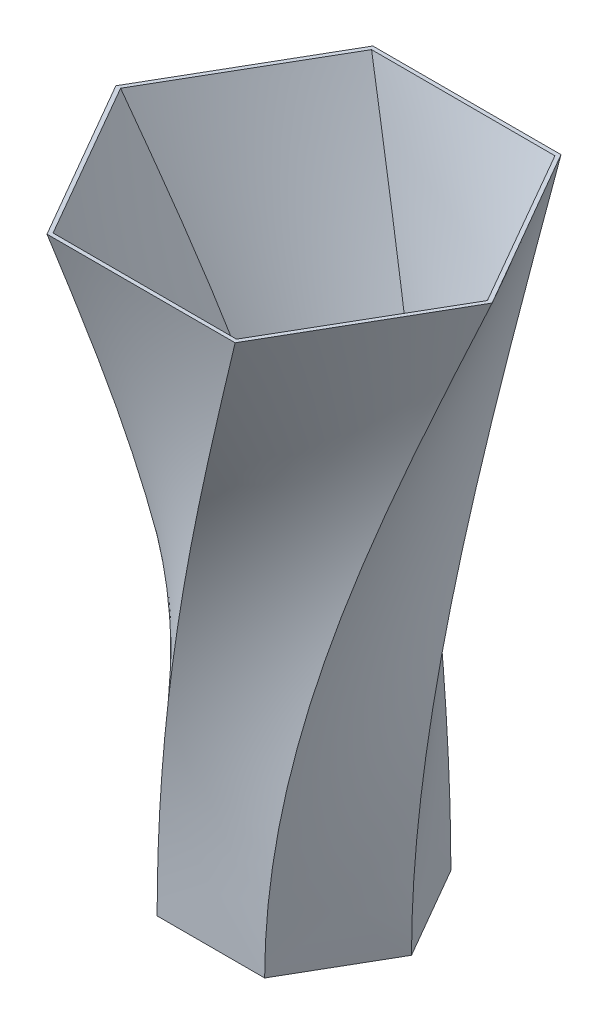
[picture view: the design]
ISO-10303-21;
HEADER;
FILE_DESCRIPTION(('STEP AP214'),'2;1');
FILE_NAME('part.step','',(''),(''),'','','');
FILE_SCHEMA(('AUTOMOTIVE_DESIGN { 1 0 10303 214 1 1 1 1 }'));
ENDSEC;
DATA;
#1=APPLICATION_CONTEXT('core data for automotive mechanical design processes');
#2=APPLICATION_PROTOCOL_DEFINITION('international standard','automotive_design',2000,#1);
#3=PRODUCT_CONTEXT('',#1,'mechanical');
#4=PRODUCT('Part','Part','',(#3));
#5=PRODUCT_RELATED_PRODUCT_CATEGORY('part','',(#4));
#6=PRODUCT_DEFINITION_FORMATION('','',#4);
#7=PRODUCT_DEFINITION_CONTEXT('part definition',#1,'design');
#8=PRODUCT_DEFINITION('design','',#6,#7);
#9=PRODUCT_DEFINITION_SHAPE('','',#8);
#10=(LENGTH_UNIT() NAMED_UNIT(*) SI_UNIT(.MILLI.,.METRE.));
#11=(NAMED_UNIT(*) PLANE_ANGLE_UNIT() SI_UNIT($,.RADIAN.));
#12=(NAMED_UNIT(*) SI_UNIT($,.STERADIAN.) SOLID_ANGLE_UNIT());
#13=UNCERTAINTY_MEASURE_WITH_UNIT(LENGTH_MEASURE(1.E-05),#10,'distance_accuracy_value','');
#14=(GEOMETRIC_REPRESENTATION_CONTEXT(3) GLOBAL_UNCERTAINTY_ASSIGNED_CONTEXT((#13)) GLOBAL_UNIT_ASSIGNED_CONTEXT((#10,
#11,#12)) REPRESENTATION_CONTEXT('',''));
#15=CARTESIAN_POINT('',(0.,0.,0.));
#16=DIRECTION('',(0.,0.,1.));
#17=DIRECTION('',(1.,0.,0.));
#18=AXIS2_PLACEMENT_3D('',#15,#16,#17);
#19=CARTESIAN_POINT('',(0.,325.,0.));
#20=DIRECTION('',(0.,1.,0.));
#21=DIRECTION('',(0.,0.,1.));
#22=AXIS2_PLACEMENT_3D('',#19,#20,#21);
#23=PLANE('',#22);
#24=CARTESIAN_POINT('',(98.6158699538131,325.,0.128719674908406));
#25=CARTESIAN_POINT('',(94.3670962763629,325.,-7.26044363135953));
#26=CARTESIAN_POINT('',(90.117498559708,325.,-14.6491331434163));
#27=CARTESIAN_POINT('',(81.6165698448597,325.,-29.4255150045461));
#28=CARTESIAN_POINT('',(77.3652388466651,325.,-36.8132073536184));
#29=CARTESIAN_POINT('',(65.2183604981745,325.,-57.9152707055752));
#30=CARTESIAN_POINT('',(57.3205883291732,325.000000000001,-71.6283610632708));
#31=CARTESIAN_POINT('',(49.4194094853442,325.,-85.3394887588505));
#32=B_SPLINE_CURVE_WITH_KNOTS('',3,(#24,#25,#26,#27,#28,#29,#30,#31),.UNSPECIFIED.,.F.,.F.,(4,2,
2,4),(0.,25.5708096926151,51.1416194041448,98.6159570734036),.UNSPECIFIED.);
#33=CARTESIAN_POINT('',(98.6158699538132,325.,0.12871967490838));
#34=VERTEX_POINT('',#33);
#35=CARTESIAN_POINT('',(49.4194094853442,325.,-85.3394887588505));
#36=VERTEX_POINT('',#35);
#37=EDGE_CURVE('E525',#34,#36,#32,.T.);
#38=ORIENTED_EDGE('',*,*,#37,.F.);
#39=CARTESIAN_POINT('',(49.196460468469,325.,85.4682084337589));
#40=CARTESIAN_POINT('',(53.4712767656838,325.,78.0940808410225));
#41=CARTESIAN_POINT('',(57.7452707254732,325.,70.7194765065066));
#42=CARTESIAN_POINT('',(66.291528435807,325.,55.9692653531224));
#43=CARTESIAN_POINT('',(70.5637921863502,325.,48.5936585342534));
#44=CARTESIAN_POINT('',(82.765275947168,325.,27.523121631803));
#45=CARTESIAN_POINT('',(90.6922744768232,324.999999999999,13.8269051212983));
#46=CARTESIAN_POINT('',(98.6158699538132,325.,0.128719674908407));
#47=B_SPLINE_CURVE_WITH_KNOTS('',3,(#39,#40,#41,#42,#43,#44,#45,#46),.UNSPECIFIED.,.F.,.F.,(4,2,
2,4),(0.,25.5708096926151,51.1416194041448,98.6159570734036),.UNSPECIFIED.);
#48=CARTESIAN_POINT('',(49.196460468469,325.,85.4682084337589));
#49=VERTEX_POINT('',#48);
#50=EDGE_CURVE('E190',#49,#34,#47,.T.);
#51=ORIENTED_EDGE('',*,*,#50,.F.);
#52=CARTESIAN_POINT('',(-49.4194094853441,325.,85.3394887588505));
#53=CARTESIAN_POINT('',(-40.8958195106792,325.,85.3545244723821));
#54=CARTESIAN_POINT('',(-32.3722278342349,325.,85.3686096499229));
#55=CARTESIAN_POINT('',(-15.3250414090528,325.,85.3947803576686));
#56=CARTESIAN_POINT('',(-6.80144666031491,325.,85.4068658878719));
#57=CARTESIAN_POINT('',(17.5469154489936,325.,85.4383923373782));
#58=CARTESIAN_POINT('',(33.3716861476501,325.,85.4552661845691));
#59=CARTESIAN_POINT('',(49.196460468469,325.,85.468208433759));
#60=B_SPLINE_CURVE_WITH_KNOTS('',3,(#52,#53,#54,#55,#56,#57,#58,#59),.UNSPECIFIED.,.F.,.F.,(4,2,
2,4),(0.,25.5708096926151,51.1416194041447,98.6159570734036),.UNSPECIFIED.);
#61=CARTESIAN_POINT('',(-49.4194094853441,325.,85.3394887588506));
#62=VERTEX_POINT('',#61);
#63=EDGE_CURVE('E92',#62,#49,#60,.T.);
#64=ORIENTED_EDGE('',*,*,#63,.F.);
#65=CARTESIAN_POINT('',(-98.6158699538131,325.,-0.128719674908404));
#66=CARTESIAN_POINT('',(-94.3670962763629,325.,7.2604436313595));
#67=CARTESIAN_POINT('',(-90.117498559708,325.,14.6491331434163));
#68=CARTESIAN_POINT('',(-81.6165698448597,325.,29.4255150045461));
#69=CARTESIAN_POINT('',(-77.365238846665,325.,36.8132073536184));
#70=CARTESIAN_POINT('',(-65.2183604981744,325.,57.9152707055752));
#71=CARTESIAN_POINT('',(-57.3205883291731,325.000000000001,71.6283610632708));
#72=CARTESIAN_POINT('',(-49.419409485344,325.,85.3394887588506));
#73=B_SPLINE_CURVE_WITH_KNOTS('',3,(#65,#66,#67,#68,#69,#70,#71,#72),.UNSPECIFIED.,.F.,.F.,(4,2,
2,4),(0.,25.5708096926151,51.1416194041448,98.6159570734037),.UNSPECIFIED.);
#74=CARTESIAN_POINT('',(-98.6158699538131,325.,-0.128719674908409));
#75=VERTEX_POINT('',#74);
#76=EDGE_CURVE('E501',#75,#62,#73,.T.);
#77=ORIENTED_EDGE('',*,*,#76,.F.);
#78=CARTESIAN_POINT('',(-49.196460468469,325.,-85.468208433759));
#79=CARTESIAN_POINT('',(-53.4712767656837,325.,-78.0940808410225));
#80=CARTESIAN_POINT('',(-57.7452707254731,325.,-70.7194765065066));
#81=CARTESIAN_POINT('',(-66.2915284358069,325.,-55.9692653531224));
#82=CARTESIAN_POINT('',(-70.5637921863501,325.,-48.5936585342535));
#83=CARTESIAN_POINT('',(-82.765275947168,325.,-27.523121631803));
#84=CARTESIAN_POINT('',(-90.6922744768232,325.,-13.8269051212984));
#85=CARTESIAN_POINT('',(-98.6158699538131,325.,-0.128719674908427));
#86=B_SPLINE_CURVE_WITH_KNOTS('',3,(#78,#79,#80,#81,#82,#83,#84,#85),.UNSPECIFIED.,.F.,.F.,(4,2,
2,4),(0.,25.5708096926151,51.1416194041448,98.6159570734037),.UNSPECIFIED.);
#87=CARTESIAN_POINT('',(-49.196460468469,325.,-85.4682084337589));
#88=VERTEX_POINT('',#87);
#89=EDGE_CURVE('E548',#88,#75,#86,.T.);
#90=ORIENTED_EDGE('',*,*,#89,.F.);
#91=CARTESIAN_POINT('',(49.4194094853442,325.,-85.3394887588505));
#92=CARTESIAN_POINT('',(40.8958195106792,325.,-85.354524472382));
#93=CARTESIAN_POINT('',(32.3722278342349,325.,-85.3686096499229));
#94=CARTESIAN_POINT('',(15.3250414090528,325.,-85.3947803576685));
#95=CARTESIAN_POINT('',(6.80144666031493,325.,-85.4068658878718));
#96=CARTESIAN_POINT('',(-17.5469154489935,325.,-85.4383923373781));
#97=CARTESIAN_POINT('',(-33.37168614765,325.,-85.4552661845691));
#98=CARTESIAN_POINT('',(-49.196460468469,325.,-85.4682084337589));
#99=B_SPLINE_CURVE_WITH_KNOTS('',3,(#91,#92,#93,#94,#95,#96,#97,#98),.UNSPECIFIED.,.F.,.F.,(4,2,
2,4),(0.,25.5708096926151,51.1416194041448,98.6159570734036),.UNSPECIFIED.);
#100=EDGE_CURVE('E542',#36,#88,#99,.T.);
#101=ORIENTED_EDGE('',*,*,#100,.F.);
#102=EDGE_LOOP('',(#38,#51,#64,#77,#90,#101));
#103=FACE_BOUND('',#102,.T.);
#104=DIRECTION('',(-0.5,0.,-0.866025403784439));
#105=VECTOR('',#104,1.);
#106=CARTESIAN_POINT('',(101.036297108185,325.,0.));
#107=LINE('',#106,#105);
#108=CARTESIAN_POINT('',(101.036297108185,325.,0.));
#109=VERTEX_POINT('',#108);
#110=CARTESIAN_POINT('',(50.5181485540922,325.,-87.5));
#111=VERTEX_POINT('',#110);
#112=EDGE_CURVE('E471',#109,#111,#107,.T.);
#113=ORIENTED_EDGE('',*,*,#112,.T.);
#114=DIRECTION('',(-1.,0.,0.));
#115=VECTOR('',#114,1.);
#116=CARTESIAN_POINT('',(50.5181485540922,325.,-87.5));
#117=LINE('',#116,#115);
#118=CARTESIAN_POINT('',(-50.5181485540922,325.,-87.5));
#119=VERTEX_POINT('',#118);
#120=EDGE_CURVE('E265',#111,#119,#117,.T.);
#121=ORIENTED_EDGE('',*,*,#120,.T.);
#122=DIRECTION('',(-0.5,0.,0.866025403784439));
#123=VECTOR('',#122,1.);
#124=CARTESIAN_POINT('',(-50.5181485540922,325.,-87.5));
#125=LINE('',#124,#123);
#126=CARTESIAN_POINT('',(-101.036297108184,325.,0.));
#127=VERTEX_POINT('',#126);
#128=EDGE_CURVE('E704',#119,#127,#125,.T.);
#129=ORIENTED_EDGE('',*,*,#128,.T.);
#130=DIRECTION('',(0.5,0.,0.866025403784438));
#131=VECTOR('',#130,1.);
#132=CARTESIAN_POINT('',(-101.036297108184,325.,0.));
#133=LINE('',#132,#131);
#134=CARTESIAN_POINT('',(-50.5181485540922,325.,87.5));
#135=VERTEX_POINT('',#134);
#136=EDGE_CURVE('E711',#127,#135,#133,.T.);
#137=ORIENTED_EDGE('',*,*,#136,.T.);
#138=DIRECTION('',(1.,0.,0.));
#139=VECTOR('',#138,1.);
#140=CARTESIAN_POINT('',(-50.5181485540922,325.,87.5));
#141=LINE('',#140,#139);
#142=CARTESIAN_POINT('',(50.5181485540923,325.,87.5));
#143=VERTEX_POINT('',#142);
#144=EDGE_CURVE('E84',#135,#143,#141,.T.);
#145=ORIENTED_EDGE('',*,*,#144,.T.);
#146=DIRECTION('',(0.5,0.,-0.866025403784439));
#147=VECTOR('',#146,1.);
#148=CARTESIAN_POINT('',(50.5181485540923,325.,87.5));
#149=LINE('',#148,#147);
#150=EDGE_CURVE('E12',#143,#109,#149,.T.);
#151=ORIENTED_EDGE('',*,*,#150,.T.);
#152=EDGE_LOOP('',(#113,#121,#129,#137,#145,#151));
#153=FACE_BOUND('',#152,.T.);
#154=ADVANCED_FACE('F74',(#103,#153),#23,.T.);
#155=CARTESIAN_POINT('',(0.,0.,0.));
#156=DIRECTION('',(0.,1.,0.));
#157=DIRECTION('',(0.,0.,1.));
#158=AXIS2_PLACEMENT_3D('',#155,#156,#157);
#159=PLANE('',#158);
#160=DIRECTION('',(-0.5,0.,-0.866025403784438));
#161=VECTOR('',#160,1.);
#162=CARTESIAN_POINT('',(57.7350269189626,0.,0.));
#163=LINE('',#162,#161);
#164=CARTESIAN_POINT('',(57.7350269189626,0.,0.));
#165=VERTEX_POINT('',#164);
#166=CARTESIAN_POINT('',(28.8675134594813,0.,-50.));
#167=VERTEX_POINT('',#166);
#168=EDGE_CURVE('E395',#165,#167,#163,.T.);
#169=ORIENTED_EDGE('',*,*,#168,.F.);
#170=DIRECTION('',(0.5,0.,-0.866025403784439));
#171=VECTOR('',#170,1.);
#172=CARTESIAN_POINT('',(28.8675134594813,0.,50.));
#173=LINE('',#172,#171);
#174=CARTESIAN_POINT('',(28.8675134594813,0.,50.));
#175=VERTEX_POINT('',#174);
#176=EDGE_CURVE('E398',#175,#165,#173,.T.);
#177=ORIENTED_EDGE('',*,*,#176,.F.);
#178=DIRECTION('',(1.,0.,0.));
#179=VECTOR('',#178,1.);
#180=CARTESIAN_POINT('',(-28.8675134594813,0.,50.));
#181=LINE('',#180,#179);
#182=CARTESIAN_POINT('',(-28.8675134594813,0.,50.));
#183=VERTEX_POINT('',#182);
#184=EDGE_CURVE('E403',#183,#175,#181,.T.);
#185=ORIENTED_EDGE('',*,*,#184,.F.);
#186=DIRECTION('',(0.5,0.,0.866025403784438));
#187=VECTOR('',#186,1.);
#188=CARTESIAN_POINT('',(-57.7350269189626,0.,0.));
#189=LINE('',#188,#187);
#190=CARTESIAN_POINT('',(-57.7350269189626,0.,0.));
#191=VERTEX_POINT('',#190);
#192=EDGE_CURVE('E458',#191,#183,#189,.T.);
#193=ORIENTED_EDGE('',*,*,#192,.F.);
#194=DIRECTION('',(-0.5,0.,0.866025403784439));
#195=VECTOR('',#194,1.);
#196=CARTESIAN_POINT('',(-28.8675134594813,0.,-50.));
#197=LINE('',#196,#195);
#198=CARTESIAN_POINT('',(-28.8675134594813,0.,-50.));
#199=VERTEX_POINT('',#198);
#200=EDGE_CURVE('E345',#199,#191,#197,.T.);
#201=ORIENTED_EDGE('',*,*,#200,.F.);
#202=DIRECTION('',(-1.,0.,0.));
#203=VECTOR('',#202,1.);
#204=CARTESIAN_POINT('',(28.8675134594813,0.,-50.));
#205=LINE('',#204,#203);
#206=EDGE_CURVE('E322',#167,#199,#205,.T.);
#207=ORIENTED_EDGE('',*,*,#206,.F.);
#208=EDGE_LOOP('',(#169,#177,#185,#193,#201,#207));
#209=FACE_BOUND('',#208,.T.);
#210=ADVANCED_FACE('F415',(#209),#159,.F.);
#211=CARTESIAN_POINT('',(-28.8675134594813,0.,50.));
#212=CARTESIAN_POINT('',(-28.8675134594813,112.216721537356,50.));
#213=CARTESIAN_POINT('',(10.8253175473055,218.608360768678,68.75));
#214=CARTESIAN_POINT('',(50.5181485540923,325.,87.5));
#215=CARTESIAN_POINT('',(-9.62250448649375,0.,50.));
#216=CARTESIAN_POINT('',(-9.62250448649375,112.216721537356,50.));
#217=CARTESIAN_POINT('',(28.8675134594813,218.608360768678,54.1666666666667));
#218=CARTESIAN_POINT('',(67.3575314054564,325.,58.3333333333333));
#219=CARTESIAN_POINT('',(9.62250448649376,0.,50.));
#220=CARTESIAN_POINT('',(9.62250448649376,112.216721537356,50.));
#221=CARTESIAN_POINT('',(46.9097093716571,218.608360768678,39.5833333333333));
#222=CARTESIAN_POINT('',(84.1969142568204,325.,29.1666666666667));
#223=CARTESIAN_POINT('',(28.8675134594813,0.,50.));
#224=CARTESIAN_POINT('',(28.8675134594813,112.216721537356,50.));
#225=CARTESIAN_POINT('',(64.9519052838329,218.608360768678,25.));
#226=CARTESIAN_POINT('',(101.036297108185,325.,0.));
#227=B_SPLINE_SURFACE_WITH_KNOTS('',3,3,((#211,#212,#213,#214),(#215,#216,#217,#218),(#219,#220,
#221,#222),(#223,#224,#225,#226)),.UNSPECIFIED.,.F.,.F.,.F.,(4,4),(4,4),(0.,1.),(0.,1.),.UNSPECIFIED.);
#228=CARTESIAN_POINT('',(28.8675134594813,0.,50.));
#229=CARTESIAN_POINT('',(28.8675134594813,112.216721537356,50.));
#230=CARTESIAN_POINT('',(64.9519052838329,218.608360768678,25.));
#231=CARTESIAN_POINT('',(101.036297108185,325.,0.));
#232=B_SPLINE_CURVE_WITH_KNOTS('',3,(#228,#229,#230,#231),.UNSPECIFIED.,.F.,.F.,(4,4),(0.,1.),.UNSPECIFIED.);
#233=EDGE_CURVE('E467',#175,#109,#232,.T.);
#234=CARTESIAN_POINT('',(-28.8675134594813,0.,50.));
#235=CARTESIAN_POINT('',(-28.8675134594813,112.216721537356,50.));
#236=CARTESIAN_POINT('',(10.8253175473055,218.608360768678,68.75));
#237=CARTESIAN_POINT('',(50.5181485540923,325.,87.5));
#238=B_SPLINE_CURVE_WITH_KNOTS('',3,(#234,#235,#236,#237),.UNSPECIFIED.,.F.,.F.,(4,4),(0.,1.),.UNSPECIFIED.);
#239=EDGE_CURVE('E402',#143,#183,#238,.F.);
#240=ORIENTED_EDGE('',*,*,#184,.T.);
#241=ORIENTED_EDGE('',*,*,#233,.T.);
#242=ORIENTED_EDGE('',*,*,#150,.F.);
#243=ORIENTED_EDGE('',*,*,#239,.T.);
#244=EDGE_LOOP('',(#240,#241,#242,#243));
#245=FACE_BOUND('',#244,.T.);
#246=ADVANCED_FACE('F234',(#245),#227,.T.);
#247=CARTESIAN_POINT('',(28.8675134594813,0.,50.));
#248=CARTESIAN_POINT('',(28.8675134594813,112.216721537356,50.));
#249=CARTESIAN_POINT('',(64.9519052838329,218.608360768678,25.));
#250=CARTESIAN_POINT('',(101.036297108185,325.,0.));
#251=CARTESIAN_POINT('',(38.4900179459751,0.,33.3333333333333));
#252=CARTESIAN_POINT('',(38.4900179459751,112.216721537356,33.3333333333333));
#253=CARTESIAN_POINT('',(61.3434661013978,218.608360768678,2.08333333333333));
#254=CARTESIAN_POINT('',(84.1969142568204,325.,-29.1666666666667));
#255=CARTESIAN_POINT('',(48.1125224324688,0.,16.6666666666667));
#256=CARTESIAN_POINT('',(48.1125224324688,112.216721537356,16.6666666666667));
#257=CARTESIAN_POINT('',(57.7350269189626,218.608360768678,-20.8333333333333));
#258=CARTESIAN_POINT('',(67.3575314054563,325.,-58.3333333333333));
#259=CARTESIAN_POINT('',(57.7350269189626,0.,0.));
#260=CARTESIAN_POINT('',(57.7350269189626,112.216721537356,0.));
#261=CARTESIAN_POINT('',(54.1265877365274,218.608360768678,-43.75));
#262=CARTESIAN_POINT('',(50.5181485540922,325.,-87.5));
#263=B_SPLINE_SURFACE_WITH_KNOTS('',3,3,((#247,#248,#249,#250),(#251,#252,#253,#254),(#255,#256,
#257,#258),(#259,#260,#261,#262)),.UNSPECIFIED.,.F.,.F.,.F.,(4,4),(4,4),(0.,1.),(0.,1.),.UNSPECIFIED.);
#264=CARTESIAN_POINT('',(57.7350269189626,0.,0.));
#265=CARTESIAN_POINT('',(57.7350269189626,112.216721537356,0.));
#266=CARTESIAN_POINT('',(54.1265877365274,218.608360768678,-43.75));
#267=CARTESIAN_POINT('',(50.5181485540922,325.,-87.5));
#268=B_SPLINE_CURVE_WITH_KNOTS('',3,(#264,#265,#266,#267),.UNSPECIFIED.,.F.,.F.,(4,4),(0.,1.),.UNSPECIFIED.);
#269=EDGE_CURVE('E309',#165,#111,#268,.T.);
#270=ORIENTED_EDGE('',*,*,#176,.T.);
#271=ORIENTED_EDGE('',*,*,#269,.T.);
#272=ORIENTED_EDGE('',*,*,#112,.F.);
#273=ORIENTED_EDGE('',*,*,#233,.F.);
#274=EDGE_LOOP('',(#270,#271,#272,#273));
#275=FACE_BOUND('',#274,.T.);
#276=ADVANCED_FACE('F227',(#275),#263,.T.);
#277=CARTESIAN_POINT('',(-57.7350269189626,0.,0.));
#278=CARTESIAN_POINT('',(-57.7350269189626,112.216721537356,0.));
#279=CARTESIAN_POINT('',(-54.1265877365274,218.608360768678,43.75));
#280=CARTESIAN_POINT('',(-50.5181485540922,325.,87.5));
#281=CARTESIAN_POINT('',(-48.1125224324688,0.,16.6666666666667));
#282=CARTESIAN_POINT('',(-48.1125224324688,112.216721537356,16.6666666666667));
#283=CARTESIAN_POINT('',(-32.4759526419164,218.608360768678,52.0833333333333));
#284=CARTESIAN_POINT('',(-16.839382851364,325.,87.5));
#285=CARTESIAN_POINT('',(-38.490017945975,0.,33.3333333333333));
#286=CARTESIAN_POINT('',(-38.490017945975,112.216721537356,33.3333333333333));
#287=CARTESIAN_POINT('',(-10.8253175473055,218.608360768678,60.4166666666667));
#288=CARTESIAN_POINT('',(16.8393828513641,325.,87.5));
#289=CARTESIAN_POINT('',(-28.8675134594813,0.,50.));
#290=CARTESIAN_POINT('',(-28.8675134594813,112.216721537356,50.));
#291=CARTESIAN_POINT('',(10.8253175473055,218.608360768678,68.75));
#292=CARTESIAN_POINT('',(50.5181485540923,325.,87.5));
#293=B_SPLINE_SURFACE_WITH_KNOTS('',3,3,((#277,#278,#279,#280),(#281,#282,#283,#284),(#285,#286,
#287,#288),(#289,#290,#291,#292)),.UNSPECIFIED.,.F.,.F.,.F.,(4,4),(4,4),(0.,1.),(0.,1.),.UNSPECIFIED.);
#294=CARTESIAN_POINT('',(-57.7350269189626,0.,0.));
#295=CARTESIAN_POINT('',(-57.7350269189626,112.216721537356,0.));
#296=CARTESIAN_POINT('',(-54.1265877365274,218.608360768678,43.75));
#297=CARTESIAN_POINT('',(-50.5181485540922,325.,87.5));
#298=B_SPLINE_CURVE_WITH_KNOTS('',3,(#294,#295,#296,#297),.UNSPECIFIED.,.F.,.F.,(4,4),(0.,1.),.UNSPECIFIED.);
#299=EDGE_CURVE('E333',#191,#135,#298,.T.);
#300=ORIENTED_EDGE('',*,*,#192,.T.);
#301=ORIENTED_EDGE('',*,*,#239,.F.);
#302=ORIENTED_EDGE('',*,*,#144,.F.);
#303=ORIENTED_EDGE('',*,*,#299,.F.);
#304=EDGE_LOOP('',(#300,#301,#302,#303));
#305=FACE_BOUND('',#304,.T.);
#306=ADVANCED_FACE('F233',(#305),#293,.T.);
#307=CARTESIAN_POINT('',(57.7350269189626,0.,0.));
#308=CARTESIAN_POINT('',(57.7350269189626,112.216721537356,0.));
#309=CARTESIAN_POINT('',(54.1265877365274,218.608360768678,-43.75));
#310=CARTESIAN_POINT('',(50.5181485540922,325.,-87.5));
#311=CARTESIAN_POINT('',(48.1125224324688,0.,-16.6666666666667));
#312=CARTESIAN_POINT('',(48.1125224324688,112.216721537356,-16.6666666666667));
#313=CARTESIAN_POINT('',(32.4759526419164,218.608360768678,-52.0833333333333));
#314=CARTESIAN_POINT('',(16.8393828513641,325.,-87.5));
#315=CARTESIAN_POINT('',(38.4900179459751,0.,-33.3333333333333));
#316=CARTESIAN_POINT('',(38.4900179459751,112.216721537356,-33.3333333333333));
#317=CARTESIAN_POINT('',(10.8253175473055,218.608360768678,-60.4166666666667));
#318=CARTESIAN_POINT('',(-16.8393828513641,325.,-87.5));
#319=CARTESIAN_POINT('',(28.8675134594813,0.,-50.));
#320=CARTESIAN_POINT('',(28.8675134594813,112.216721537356,-50.));
#321=CARTESIAN_POINT('',(-10.8253175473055,218.608360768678,-68.75));
#322=CARTESIAN_POINT('',(-50.5181485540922,325.,-87.5));
#323=B_SPLINE_SURFACE_WITH_KNOTS('',3,3,((#307,#308,#309,#310),(#311,#312,#313,#314),(#315,#316,
#317,#318),(#319,#320,#321,#322)),.UNSPECIFIED.,.F.,.F.,.F.,(4,4),(4,4),(0.,1.),(0.,1.),.UNSPECIFIED.);
#324=CARTESIAN_POINT('',(28.8675134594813,0.,-50.));
#325=CARTESIAN_POINT('',(28.8675134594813,112.216721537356,-50.));
#326=CARTESIAN_POINT('',(-10.8253175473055,218.608360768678,-68.75));
#327=CARTESIAN_POINT('',(-50.5181485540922,325.,-87.5));
#328=B_SPLINE_CURVE_WITH_KNOTS('',3,(#324,#325,#326,#327),.UNSPECIFIED.,.F.,.F.,(4,4),(0.,1.),.UNSPECIFIED.);
#329=EDGE_CURVE('E301',#167,#119,#328,.T.);
#330=ORIENTED_EDGE('',*,*,#168,.T.);
#331=ORIENTED_EDGE('',*,*,#329,.T.);
#332=ORIENTED_EDGE('',*,*,#120,.F.);
#333=ORIENTED_EDGE('',*,*,#269,.F.);
#334=EDGE_LOOP('',(#330,#331,#332,#333));
#335=FACE_BOUND('',#334,.T.);
#336=ADVANCED_FACE('F271',(#335),#323,.T.);
#337=CARTESIAN_POINT('',(28.8675134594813,0.,-50.));
#338=CARTESIAN_POINT('',(28.8675134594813,112.216721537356,-50.));
#339=CARTESIAN_POINT('',(-10.8253175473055,218.608360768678,-68.75));
#340=CARTESIAN_POINT('',(-50.5181485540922,325.,-87.5));
#341=CARTESIAN_POINT('',(9.62250448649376,0.,-50.));
#342=CARTESIAN_POINT('',(9.62250448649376,112.216721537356,-50.));
#343=CARTESIAN_POINT('',(-28.8675134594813,218.608360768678,-54.1666666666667));
#344=CARTESIAN_POINT('',(-67.3575314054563,325.,-58.3333333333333));
#345=CARTESIAN_POINT('',(-9.62250448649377,0.,-50.));
#346=CARTESIAN_POINT('',(-9.62250448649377,112.216721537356,-50.));
#347=CARTESIAN_POINT('',(-46.9097093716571,218.608360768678,-39.5833333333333));
#348=CARTESIAN_POINT('',(-84.1969142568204,325.,-29.1666666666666));
#349=CARTESIAN_POINT('',(-28.8675134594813,0.,-50.));
#350=CARTESIAN_POINT('',(-28.8675134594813,112.216721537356,-50.));
#351=CARTESIAN_POINT('',(-64.9519052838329,218.608360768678,-25.));
#352=CARTESIAN_POINT('',(-101.036297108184,325.,0.));
#353=B_SPLINE_SURFACE_WITH_KNOTS('',3,3,((#337,#338,#339,#340),(#341,#342,#343,#344),(#345,#346,
#347,#348),(#349,#350,#351,#352)),.UNSPECIFIED.,.F.,.F.,.F.,(4,4),(4,4),(0.,1.),(0.,1.),.UNSPECIFIED.);
#354=CARTESIAN_POINT('',(-28.8675134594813,0.,-50.));
#355=CARTESIAN_POINT('',(-28.8675134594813,112.216721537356,-50.));
#356=CARTESIAN_POINT('',(-64.9519052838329,218.608360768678,-25.));
#357=CARTESIAN_POINT('',(-101.036297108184,325.,0.));
#358=B_SPLINE_CURVE_WITH_KNOTS('',3,(#354,#355,#356,#357),.UNSPECIFIED.,.F.,.F.,(4,4),(0.,1.),.UNSPECIFIED.);
#359=EDGE_CURVE('E308',#199,#127,#358,.T.);
#360=ORIENTED_EDGE('',*,*,#206,.T.);
#361=ORIENTED_EDGE('',*,*,#359,.T.);
#362=ORIENTED_EDGE('',*,*,#128,.F.);
#363=ORIENTED_EDGE('',*,*,#329,.F.);
#364=EDGE_LOOP('',(#360,#361,#362,#363));
#365=FACE_BOUND('',#364,.T.);
#366=ADVANCED_FACE('F282',(#365),#353,.T.);
#367=CARTESIAN_POINT('',(-28.8675134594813,0.,-50.));
#368=CARTESIAN_POINT('',(-28.8675134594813,112.216721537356,-50.));
#369=CARTESIAN_POINT('',(-64.9519052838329,218.608360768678,-25.));
#370=CARTESIAN_POINT('',(-101.036297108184,325.,0.));
#371=CARTESIAN_POINT('',(-38.4900179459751,0.,-33.3333333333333));
#372=CARTESIAN_POINT('',(-38.4900179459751,112.216721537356,-33.3333333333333));
#373=CARTESIAN_POINT('',(-61.3434661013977,218.608360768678,-2.08333333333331));
#374=CARTESIAN_POINT('',(-84.1969142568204,325.,29.1666666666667));
#375=CARTESIAN_POINT('',(-48.1125224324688,0.,-16.6666666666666));
#376=CARTESIAN_POINT('',(-48.1125224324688,112.216721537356,-16.6666666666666));
#377=CARTESIAN_POINT('',(-57.7350269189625,218.608360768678,20.8333333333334));
#378=CARTESIAN_POINT('',(-67.3575314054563,325.,58.3333333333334));
#379=CARTESIAN_POINT('',(-57.7350269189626,0.,0.));
#380=CARTESIAN_POINT('',(-57.7350269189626,112.216721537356,0.));
#381=CARTESIAN_POINT('',(-54.1265877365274,218.608360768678,43.75));
#382=CARTESIAN_POINT('',(-50.5181485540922,325.,87.5));
#383=B_SPLINE_SURFACE_WITH_KNOTS('',3,3,((#367,#368,#369,#370),(#371,#372,#373,#374),(#375,#376,
#377,#378),(#379,#380,#381,#382)),.UNSPECIFIED.,.F.,.F.,.F.,(4,4),(4,4),(0.,1.),(0.,1.),.UNSPECIFIED.);
#384=ORIENTED_EDGE('',*,*,#200,.T.);
#385=ORIENTED_EDGE('',*,*,#299,.T.);
#386=ORIENTED_EDGE('',*,*,#136,.F.);
#387=ORIENTED_EDGE('',*,*,#359,.F.);
#388=EDGE_LOOP('',(#384,#385,#386,#387));
#389=FACE_BOUND('',#388,.T.);
#390=ADVANCED_FACE('F351',(#389),#383,.T.);
#391=CARTESIAN_POINT('',(0.,7.5,0.));
#392=DIRECTION('',(0.,1.,0.));
#393=DIRECTION('',(0.,0.,1.));
#394=AXIS2_PLACEMENT_3D('',#391,#392,#393);
#395=PLANE('',#394);
#396=CARTESIAN_POINT('',(55.4202012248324,7.5,-0.0622549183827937));
#397=CARTESIAN_POINT('',(50.7929049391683,7.5,-8.05630691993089));
#398=CARTESIAN_POINT('',(46.1655888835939,7.5,-16.0503474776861));
#399=CARTESIAN_POINT('',(36.9109172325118,7.5,-32.0384057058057));
#400=CARTESIAN_POINT('',(32.2835616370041,7.5,-40.0324233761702));
#401=CARTESIAN_POINT('',(27.6561862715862,7.5,-48.0264296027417));
#402=B_SPLINE_CURVE_WITH_KNOTS('',3,(#396,#397,#398,#399,#400,#401),.UNSPECIFIED.,.F.,.F.,(4,2,
4),(0.,27.7101180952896,55.4202361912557),.UNSPECIFIED.);
#403=CARTESIAN_POINT('',(55.4202012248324,7.5,-0.0622549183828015));
#404=VERTEX_POINT('',#403);
#405=CARTESIAN_POINT('',(27.6561862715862,7.5,-48.0264296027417));
#406=VERTEX_POINT('',#405);
#407=EDGE_CURVE('E565',#404,#406,#402,.T.);
#408=ORIENTED_EDGE('',*,*,#407,.T.);
#409=CARTESIAN_POINT('',(27.6561862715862,7.5,-48.0264296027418));
#410=CARTESIAN_POINT('',(18.4194860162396,7.5,-48.0160994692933));
#411=CARTESIAN_POINT('',(9.18278578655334,7.5,-48.0057464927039));
#412=CARTESIAN_POINT('',(-9.29061462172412,7.5,-47.9849948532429));
#413=CARTESIAN_POINT('',(-18.5273148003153,7.5,-47.9745961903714));
#414=CARTESIAN_POINT('',(-27.7640149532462,7.5,-47.9641746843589));
#415=B_SPLINE_CURVE_WITH_KNOTS('',3,(#409,#410,#411,#412,#413,#414),.UNSPECIFIED.,.F.,.F.,(4,2,
4),(0.,27.7101180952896,55.4202361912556),.UNSPECIFIED.);
#416=CARTESIAN_POINT('',(-27.7640149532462,7.5,-47.9641746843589));
#417=VERTEX_POINT('',#416);
#418=EDGE_CURVE('E202',#406,#417,#415,.T.);
#419=ORIENTED_EDGE('',*,*,#418,.T.);
#420=CARTESIAN_POINT('',(-27.7640149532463,7.5,-47.9641746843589));
#421=CARTESIAN_POINT('',(-32.3734189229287,7.5,-39.9597925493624));
#422=CARTESIAN_POINT('',(-36.9828030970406,7.5,-31.9553990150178));
#423=CARTESIAN_POINT('',(-46.201531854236,7.5,-15.9465891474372));
#424=CARTESIAN_POINT('',(-50.8108764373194,7.5,-7.94217281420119));
#425=CARTESIAN_POINT('',(-55.4202012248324,7.5,0.0622549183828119));
#426=B_SPLINE_CURVE_WITH_KNOTS('',3,(#420,#421,#422,#423,#424,#425),.UNSPECIFIED.,.F.,.F.,(4,2,
4),(0.,27.7101180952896,55.4202361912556),.UNSPECIFIED.);
#427=CARTESIAN_POINT('',(-55.4202012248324,7.5,0.0622549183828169));
#428=VERTEX_POINT('',#427);
#429=EDGE_CURVE('E568',#417,#428,#426,.T.);
#430=ORIENTED_EDGE('',*,*,#429,.T.);
#431=CARTESIAN_POINT('',(-55.4202012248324,7.5,0.0622549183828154));
#432=CARTESIAN_POINT('',(-50.7929049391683,7.5,8.05630691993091));
#433=CARTESIAN_POINT('',(-46.1655888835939,7.5,16.0503474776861));
#434=CARTESIAN_POINT('',(-36.9109172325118,7.5,32.0384057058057));
#435=CARTESIAN_POINT('',(-32.2835616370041,7.5,40.0324233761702));
#436=CARTESIAN_POINT('',(-27.6561862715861,7.5,48.0264296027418));
#437=B_SPLINE_CURVE_WITH_KNOTS('',3,(#431,#432,#433,#434,#435,#436),.UNSPECIFIED.,.F.,.F.,(4,2,
4),(0.,27.7101180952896,55.4202361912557),.UNSPECIFIED.);
#438=CARTESIAN_POINT('',(-27.6561862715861,7.5,48.0264296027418));
#439=VERTEX_POINT('',#438);
#440=EDGE_CURVE('E185',#428,#439,#437,.T.);
#441=ORIENTED_EDGE('',*,*,#440,.T.);
#442=CARTESIAN_POINT('',(-27.6561862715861,7.5,48.0264296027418));
#443=CARTESIAN_POINT('',(-18.4194860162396,7.5,48.0160994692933));
#444=CARTESIAN_POINT('',(-9.18278578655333,7.5,48.0057464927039));
#445=CARTESIAN_POINT('',(9.29061462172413,7.5,47.9849948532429));
#446=CARTESIAN_POINT('',(18.5273148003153,7.5,47.9745961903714));
#447=CARTESIAN_POINT('',(27.7640149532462,7.5,47.9641746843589));
#448=B_SPLINE_CURVE_WITH_KNOTS('',3,(#442,#443,#444,#445,#446,#447),.UNSPECIFIED.,.F.,.F.,(4,2,
4),(0.,27.7101180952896,55.4202361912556),.UNSPECIFIED.);
#449=CARTESIAN_POINT('',(27.7640149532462,7.5,47.9641746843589));
#450=VERTEX_POINT('',#449);
#451=EDGE_CURVE('E180',#439,#450,#448,.T.);
#452=ORIENTED_EDGE('',*,*,#451,.T.);
#453=CARTESIAN_POINT('',(27.7640149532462,7.5,47.9641746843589));
#454=CARTESIAN_POINT('',(32.3734189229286,7.5,39.9597925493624));
#455=CARTESIAN_POINT('',(36.9828030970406,7.5,31.9553990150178));
#456=CARTESIAN_POINT('',(46.201531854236,7.5,15.9465891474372));
#457=CARTESIAN_POINT('',(50.8108764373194,7.5,7.94217281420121));
#458=CARTESIAN_POINT('',(55.4202012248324,7.5,-0.0622549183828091));
#459=B_SPLINE_CURVE_WITH_KNOTS('',3,(#453,#454,#455,#456,#457,#458),.UNSPECIFIED.,.F.,.F.,(4,2,
4),(0.,27.7101180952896,55.4202361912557),.UNSPECIFIED.);
#460=EDGE_CURVE('E168',#450,#404,#459,.T.);
#461=ORIENTED_EDGE('',*,*,#460,.T.);
#462=EDGE_LOOP('',(#408,#419,#430,#441,#452,#461));
#463=FACE_BOUND('',#462,.T.);
#464=ADVANCED_FACE('F183',(#463),#395,.T.);
#465=CARTESIAN_POINT('',(-28.8675134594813,0.,50.));
#466=CARTESIAN_POINT('',(-28.8675134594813,112.216721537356,50.));
#467=CARTESIAN_POINT('',(10.8253175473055,218.608360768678,68.75));
#468=CARTESIAN_POINT('',(50.5181485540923,325.,87.5));
#469=CARTESIAN_POINT('',(-9.62250448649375,0.,50.));
#470=CARTESIAN_POINT('',(-9.62250448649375,112.216721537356,50.));
#471=CARTESIAN_POINT('',(28.8675134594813,218.608360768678,54.1666666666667));
#472=CARTESIAN_POINT('',(67.3575314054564,325.,58.3333333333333));
#473=CARTESIAN_POINT('',(9.62250448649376,0.,50.));
#474=CARTESIAN_POINT('',(9.62250448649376,112.216721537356,50.));
#475=CARTESIAN_POINT('',(46.9097093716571,218.608360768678,39.5833333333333));
#476=CARTESIAN_POINT('',(84.1969142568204,325.,29.1666666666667));
#477=CARTESIAN_POINT('',(28.8675134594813,0.,50.));
#478=CARTESIAN_POINT('',(28.8675134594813,112.216721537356,50.));
#479=CARTESIAN_POINT('',(64.9519052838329,218.608360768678,25.));
#480=CARTESIAN_POINT('',(101.036297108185,325.,0.));
#481=B_SPLINE_SURFACE_WITH_KNOTS('',3,3,((#465,#466,#467,#468),(#469,#470,#471,#472),(#473,#474,
#475,#476),(#477,#478,#479,#480)),.UNSPECIFIED.,.F.,.F.,.F.,(4,4),(4,4),(0.,1.),(0.,1.),.UNSPECIFIED.);
#482=OFFSET_SURFACE('',#481,-2.,.F.);
#483=ORIENTED_EDGE('',*,*,#451,.F.);
#484=CARTESIAN_POINT('',(49.196460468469,325.,85.4682084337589));
#485=CARTESIAN_POINT('',(47.7460895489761,321.063491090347,84.7635392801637));
#486=CARTESIAN_POINT('',(46.2966698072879,317.126669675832,84.0586192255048));
#487=CARTESIAN_POINT('',(43.4034084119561,309.250333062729,82.6500266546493));
#488=CARTESIAN_POINT('',(41.959567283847,305.310817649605,81.9463542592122));
#489=CARTESIAN_POINT('',(39.0813385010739,297.427560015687,80.5421031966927));
#490=CARTESIAN_POINT('',(37.64695130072,293.4838176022,79.8415246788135));
#491=CARTESIAN_POINT('',(34.7915238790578,285.590560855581,78.4453703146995));
#492=CARTESIAN_POINT('',(33.370483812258,281.641046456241,77.749794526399));
#493=CARTESIAN_POINT('',(30.5403419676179,273.719822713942,76.3630120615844));
#494=CARTESIAN_POINT('',(29.1313048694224,269.748085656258,75.6718315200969));
#495=CARTESIAN_POINT('',(26.3345565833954,261.795631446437,74.2985588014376));
#496=CARTESIAN_POINT('',(24.9468449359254,257.814914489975,73.6164664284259));
#497=CARTESIAN_POINT('',(22.1966850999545,249.842897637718,72.2635144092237));
#498=CARTESIAN_POINT('',(20.8342366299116,245.85159786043,71.592654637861));
#499=CARTESIAN_POINT('',(18.1385163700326,237.856810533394,70.2643931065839));
#500=CARTESIAN_POINT('',(16.8052452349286,233.853322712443,69.606991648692));
#501=CARTESIAN_POINT('',(14.0368031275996,225.421542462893,68.2413754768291));
#502=CARTESIAN_POINT('',(12.6052074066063,220.991797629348,67.5348652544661));
#503=CARTESIAN_POINT('',(9.78756052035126,212.114234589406,66.1442738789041));
#504=CARTESIAN_POINT('',(8.40151008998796,207.666416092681,65.4601930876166));
#505=CARTESIAN_POINT('',(5.68020480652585,198.751443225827,64.1177514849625));
#506=CARTESIAN_POINT('',(4.34494923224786,194.284289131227,63.4593903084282));
#507=CARTESIAN_POINT('',(1.7303704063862,185.329429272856,62.1716155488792));
#508=CARTESIAN_POINT('',(0.451047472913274,180.84172339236,61.5422021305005));
#509=CARTESIAN_POINT('',(-2.04352637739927,171.855650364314,60.3169229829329));
#510=CARTESIAN_POINT('',(-3.25892254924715,167.357334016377,59.7209809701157));
#511=CARTESIAN_POINT('',(-5.62374581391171,158.338796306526,58.5639667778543));
#512=CARTESIAN_POINT('',(-6.77317156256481,153.818574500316,58.0028953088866));
#513=CARTESIAN_POINT('',(-9.00072166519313,144.755957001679,56.9183724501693));
#514=CARTESIAN_POINT('',(-10.078844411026,140.213560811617,56.3949219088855));
#515=CARTESIAN_POINT('',(-12.1582964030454,131.106314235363,55.3881719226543));
#516=CARTESIAN_POINT('',(-13.1596185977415,126.541461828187,54.904876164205));
#517=CARTESIAN_POINT('',(-15.1012411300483,117.286522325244,53.9704608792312));
#518=CARTESIAN_POINT('',(-16.0396483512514,112.595938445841,53.5203166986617));
#519=CARTESIAN_POINT('',(-17.823391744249,103.192748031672,52.6671169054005));
#520=CARTESIAN_POINT('',(-18.6687270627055,98.4801412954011,52.2640617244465));
#521=CARTESIAN_POINT('',(-20.2594088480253,89.0346830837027,51.5075916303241));
#522=CARTESIAN_POINT('',(-21.0047680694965,84.3018342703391,51.1541703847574));
#523=CARTESIAN_POINT('',(-22.3885645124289,74.8176662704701,50.4994866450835));
#524=CARTESIAN_POINT('',(-23.0270191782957,70.0663502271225,50.1982156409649));
#525=CARTESIAN_POINT('',(-24.1937247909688,60.5179451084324,49.6486692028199));
#526=CARTESIAN_POINT('',(-24.7212882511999,55.7207527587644,49.4007241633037));
#527=CARTESIAN_POINT('',(-25.6545029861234,46.1112878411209,48.9627287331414));
#528=CARTESIAN_POINT('',(-26.0601428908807,41.2990139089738,48.7726837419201));
#529=CARTESIAN_POINT('',(-26.5723182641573,34.0714174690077,48.5329487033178));
#530=CARTESIAN_POINT('',(-26.7270190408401,31.6601645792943,48.4605816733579));
#531=CARTESIAN_POINT('',(-27.0035284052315,26.8353464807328,48.3312866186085));
#532=CARTESIAN_POINT('',(-27.1253371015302,24.4217812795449,48.2743585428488));
#533=CARTESIAN_POINT('',(-27.3354248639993,19.5908667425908,48.1762009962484));
#534=CARTESIAN_POINT('',(-27.4236760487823,17.1735159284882,48.1349845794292));
#535=CARTESIAN_POINT('',(-27.5658463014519,12.3375551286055,48.0685998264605));
#536=CARTESIAN_POINT('',(-27.61976492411,9.91894512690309,48.043431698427));
#537=CARTESIAN_POINT('',(-27.6561862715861,7.50000000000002,48.0264296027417));
#538=B_SPLINE_CURVE_WITH_KNOTS('',3,(#484,#485,#486,#487,#488,#489,#490,#491,#492,#493,#494,
#495,#496,#497,#498,#499,#500,#501,#502,#503,#504,#505,#506,#507,#508,#509,#510,#511,#512,#513,
#514,#515,#516,#517,#518,#519,#520,#521,#522,#523,#524,#525,#526,#527,#528,#529,#530,#531,#532,
#533,#534,#535,#536,#537),.UNSPECIFIED.,.F.,.F.,(4,2,2,2,2,2,2,2,2,2,2,2,2,2,2,2,2,2,2,2,2,2,2,
2,2,2,4),(0.,12.7619118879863,25.5249980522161,38.2886931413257,51.0525358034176,
63.8642020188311,76.6755917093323,89.4868385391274,102.298372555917,116.424007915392,
130.54987108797,144.67553362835,158.801276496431,172.893397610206,186.985805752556,
201.078531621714,215.172549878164,229.58543594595,243.998454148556,258.409631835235,
272.818455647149,287.314133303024,301.811162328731,309.062818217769,316.314450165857,
323.572094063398,330.829832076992),.UNSPECIFIED.);
#539=EDGE_CURVE('E179',#49,#439,#538,.T.);
#540=ORIENTED_EDGE('',*,*,#539,.F.);
#541=ORIENTED_EDGE('',*,*,#50,.T.);
#542=CARTESIAN_POINT('',(27.7640149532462,7.5,47.9641746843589));
#543=CARTESIAN_POINT('',(27.7892043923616,9.34979276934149,47.9465515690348));
#544=CARTESIAN_POINT('',(27.8236406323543,11.1993772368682,47.9224594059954));
#545=CARTESIAN_POINT('',(27.9107573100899,14.8978964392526,47.8615220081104));
#546=CARTESIAN_POINT('',(27.9634376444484,16.7468311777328,47.8246768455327));
#547=CARTESIAN_POINT('',(28.1484221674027,22.2908707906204,47.6953233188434));
#548=CARTESIAN_POINT('',(28.3076903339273,25.9846841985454,47.5839825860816));
#549=CARTESIAN_POINT('',(28.6959232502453,33.3661046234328,47.3127630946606));
#550=CARTESIAN_POINT('',(28.9248748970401,37.0537126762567,47.1528934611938));
#551=CARTESIAN_POINT('',(29.4501239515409,44.4216285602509,46.7864553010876));
#552=CARTESIAN_POINT('',(29.7464183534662,48.1019367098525,46.5798888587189));
#553=CARTESIAN_POINT('',(30.402565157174,55.4391292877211,46.1229492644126));
#554=CARTESIAN_POINT('',(30.7621566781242,59.0960483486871,45.8727559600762));
#555=CARTESIAN_POINT('',(31.5432135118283,66.4003826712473,45.3300297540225));
#556=CARTESIAN_POINT('',(31.9646834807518,70.0477971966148,45.0374936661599));
#557=CARTESIAN_POINT('',(32.8669484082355,77.3320241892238,44.4121924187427));
#558=CARTESIAN_POINT('',(33.3477468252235,80.9688360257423,44.0794249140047));
#559=CARTESIAN_POINT('',(34.3660800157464,88.2307496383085,43.3758223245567));
#560=CARTESIAN_POINT('',(34.9036142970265,91.8558515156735,43.0049875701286));
#561=CARTESIAN_POINT('',(36.2198467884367,100.292044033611,42.0986406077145));
#562=CARTESIAN_POINT('',(37.0194647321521,105.098392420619,41.549258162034));
#563=CARTESIAN_POINT('',(38.7087971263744,114.687877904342,40.3917581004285));
#564=CARTESIAN_POINT('',(39.5985086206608,119.471015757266,39.7836424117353));
#565=CARTESIAN_POINT('',(41.4622803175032,129.013580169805,38.5133053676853));
#566=CARTESIAN_POINT('',(42.4363406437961,133.773006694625,37.8510839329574));
#567=CARTESIAN_POINT('',(44.4653425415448,143.278258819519,36.4753297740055));
#568=CARTESIAN_POINT('',(45.5204573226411,148.02403146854,35.7616873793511));
#569=CARTESIAN_POINT('',(47.7039479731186,157.491418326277,34.2883515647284));
#570=CARTESIAN_POINT('',(48.832323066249,162.213032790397,33.5286586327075));
#571=CARTESIAN_POINT('',(51.1564947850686,171.632346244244,31.9668756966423));
#572=CARTESIAN_POINT('',(52.3522886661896,176.330046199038,31.1647874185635));
#573=CARTESIAN_POINT('',(54.8630388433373,185.922623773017,29.4829733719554));
#574=CARTESIAN_POINT('',(56.1809541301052,190.816396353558,28.6013704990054));
#575=CARTESIAN_POINT('',(58.8773055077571,200.580076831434,26.7991007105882));
#576=CARTESIAN_POINT('',(60.2557427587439,205.449984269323,25.8784330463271));
#577=CARTESIAN_POINT('',(63.0662086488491,215.168042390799,24.001665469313));
#578=CARTESIAN_POINT('',(64.4982433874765,220.016190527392,23.0455615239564));
#579=CARTESIAN_POINT('',(67.4088799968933,229.692885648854,21.1016741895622));
#580=CARTESIAN_POINT('',(68.8874886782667,234.521429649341,20.1138861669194));
#581=CARTESIAN_POINT('',(71.8842357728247,244.16111088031,18.1105499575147));
#582=CARTESIAN_POINT('',(73.4023790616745,248.972245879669,17.0949983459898));
#583=CARTESIAN_POINT('',(76.4626527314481,258.552515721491,15.0459555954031));
#584=CARTESIAN_POINT('',(78.0046041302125,263.321735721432,14.012594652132));
#585=CARTESIAN_POINT('',(81.1139330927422,272.847325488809,11.9266211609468));
#586=CARTESIAN_POINT('',(82.6813091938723,277.603695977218,10.8740097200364));
#587=CARTESIAN_POINT('',(85.8348526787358,287.105745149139,8.75379462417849));
#588=CARTESIAN_POINT('',(87.4210162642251,291.851425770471,7.6861939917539));
#589=CARTESIAN_POINT('',(90.6056198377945,301.334224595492,5.54032463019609));
#590=CARTESIAN_POINT('',(92.2040551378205,306.071345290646,4.46205993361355));
#591=CARTESIAN_POINT('',(95.4068324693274,315.539127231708,2.29922478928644));
#592=CARTESIAN_POINT('',(97.0111707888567,320.269790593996,1.21465811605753));
#593=CARTESIAN_POINT('',(98.6158699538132,325.,0.12871967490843));
#594=B_SPLINE_CURVE_WITH_KNOTS('',3,(#542,#543,#544,#545,#546,#547,#548,#549,#550,#551,#552,
#553,#554,#555,#556,#557,#558,#559,#560,#561,#562,#563,#564,#565,#566,#567,#568,#569,#570,#571,
#572,#573,#574,#575,#576,#577,#578,#579,#580,#581,#582,#583,#584,#585,#586,#587,#588,#589,#590,
#591,#592,#593),.UNSPECIFIED.,.F.,.F.,(4,2,2,2,2,2,2,2,2,2,2,2,2,2,2,2,2,2,2,2,2,2,2,2,2,4),(0.,
5.55007084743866,11.1001102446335,22.1957701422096,33.2893449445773,44.3824246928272,
55.4308111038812,66.4800292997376,77.5298918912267,88.5796586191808,103.28812436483,
117.996107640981,132.704112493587,147.444472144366,162.184675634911,176.924279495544,
192.3563533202,207.788723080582,223.222854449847,238.659253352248,254.097565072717,
269.450538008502,284.802630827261,300.151671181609,315.495113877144,330.830158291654),.UNSPECIFIED.);
#595=EDGE_CURVE('E173',#450,#34,#594,.T.);
#596=ORIENTED_EDGE('',*,*,#595,.F.);
#597=EDGE_LOOP('',(#483,#540,#541,#596));
#598=FACE_BOUND('',#597,.T.);
#599=ADVANCED_FACE('F188',(#598),#482,.F.);
#600=CARTESIAN_POINT('',(28.8675134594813,0.,50.));
#601=CARTESIAN_POINT('',(28.8675134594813,112.216721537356,50.));
#602=CARTESIAN_POINT('',(64.9519052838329,218.608360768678,25.));
#603=CARTESIAN_POINT('',(101.036297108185,325.,0.));
#604=CARTESIAN_POINT('',(38.4900179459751,0.,33.3333333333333));
#605=CARTESIAN_POINT('',(38.4900179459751,112.216721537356,33.3333333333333));
#606=CARTESIAN_POINT('',(61.3434661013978,218.608360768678,2.08333333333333));
#607=CARTESIAN_POINT('',(84.1969142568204,325.,-29.1666666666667));
#608=CARTESIAN_POINT('',(48.1125224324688,0.,16.6666666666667));
#609=CARTESIAN_POINT('',(48.1125224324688,112.216721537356,16.6666666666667));
#610=CARTESIAN_POINT('',(57.7350269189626,218.608360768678,-20.8333333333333));
#611=CARTESIAN_POINT('',(67.3575314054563,325.,-58.3333333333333));
#612=CARTESIAN_POINT('',(57.7350269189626,0.,0.));
#613=CARTESIAN_POINT('',(57.7350269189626,112.216721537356,0.));
#614=CARTESIAN_POINT('',(54.1265877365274,218.608360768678,-43.75));
#615=CARTESIAN_POINT('',(50.5181485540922,325.,-87.5));
#616=B_SPLINE_SURFACE_WITH_KNOTS('',3,3,((#600,#601,#602,#603),(#604,#605,#606,#607),(#608,#609,
#610,#611),(#612,#613,#614,#615)),.UNSPECIFIED.,.F.,.F.,.F.,(4,4),(4,4),(0.,1.),(0.,1.),.UNSPECIFIED.);
#617=OFFSET_SURFACE('',#616,-2.,.F.);
#618=ORIENTED_EDGE('',*,*,#460,.F.);
#619=ORIENTED_EDGE('',*,*,#595,.T.);
#620=ORIENTED_EDGE('',*,*,#37,.T.);
#621=CARTESIAN_POINT('',(55.4202012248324,7.5,-0.0622549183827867));
#622=CARTESIAN_POINT('',(55.4175338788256,9.34979276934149,-0.0928811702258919));
#623=CARTESIAN_POINT('',(55.4138875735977,11.1993772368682,-0.134749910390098));
#624=CARTESIAN_POINT('',(55.4046725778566,14.8978964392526,-0.240663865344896));
#625=CARTESIAN_POINT('',(55.3991038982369,16.7468311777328,-0.304708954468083));
#626=CARTESIAN_POINT('',(55.379572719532,22.2908707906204,-0.529587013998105));
#627=CARTESIAN_POINT('',(55.3627828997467,25.9846841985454,-0.723187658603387));
#628=CARTESIAN_POINT('',(55.3220163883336,33.3661046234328,-1.19501697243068));
#629=CARTESIAN_POINT('',(55.298041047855,37.0537126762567,-1.47322973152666));
#630=CARTESIAN_POINT('',(55.2433208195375,44.421628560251,-2.11132783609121));
#631=CARTESIAN_POINT('',(55.2125762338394,48.1019367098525,-2.47120953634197));
#632=CARTESIAN_POINT('',(55.1449283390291,55.4391292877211,-3.26791913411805));
#633=CARTESIAN_POINT('',(55.1080503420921,59.0960483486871,-3.70443117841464));
#634=CARTESIAN_POINT('',(55.0285640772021,66.4003826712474,-4.65220934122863));
#635=CARTESIAN_POINT('',(54.9859553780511,70.0477971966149,-5.16348108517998));
#636=CARTESIAN_POINT('',(54.8955610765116,77.3320241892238,-6.25751605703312));
#637=CARTESIAN_POINT('',(54.8477751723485,80.9688360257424,-6.84028345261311));
#638=CARTESIAN_POINT('',(54.7476040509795,88.2307496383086,-8.07398715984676));
#639=CARTESIAN_POINT('',(54.6952188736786,91.8558515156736,-8.72492288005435));
#640=CARTESIAN_POINT('',(54.5684156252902,100.292044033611,-10.3179871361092));
#641=CARTESIAN_POINT('',(54.4924454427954,105.098392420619,-11.2851678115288));
#642=CARTESIAN_POINT('',(54.3346871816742,114.687877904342,-13.3269226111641));
#643=CARTESIAN_POINT('',(54.2528992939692,119.471015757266,-14.4014932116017));
#644=CARTESIAN_POINT('',(54.0846409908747,129.013580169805,-16.6507353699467));
#645=CARTESIAN_POINT('',(53.9981705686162,133.773006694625,-17.8254070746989));
#646=CARTESIAN_POINT('',(53.821233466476,143.278258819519,-20.270451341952));
#647=CARTESIAN_POINT('',(53.7307584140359,148.02403146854,-21.5410287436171));
#648=CARTESIAN_POINT('',(53.546557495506,157.491418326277,-24.1686550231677));
#649=CARTESIAN_POINT('',(53.4528316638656,162.213032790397,-25.5257029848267));
#650=CARTESIAN_POINT('',(53.2623738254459,171.632346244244,-28.3193862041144));
#651=CARTESIAN_POINT('',(53.1656419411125,176.330046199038,-29.7560182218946));
#652=CARTESIAN_POINT('',(52.9645233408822,185.922623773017,-32.7712986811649));
#653=CARTESIAN_POINT('',(52.8599905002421,190.816396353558,-34.3534482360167));
#654=CARTESIAN_POINT('',(52.6473547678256,200.580076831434,-37.589691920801));
#655=CARTESIAN_POINT('',(52.5392518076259,205.449984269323,-39.2437874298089));
#656=CARTESIAN_POINT('',(52.3191563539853,215.168042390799,-42.6161060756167));
#657=CARTESIAN_POINT('',(52.2071634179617,220.016190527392,-44.3343365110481));
#658=CARTESIAN_POINT('',(51.97902590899,229.692885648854,-47.8269654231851));
#659=CARTESIAN_POINT('',(51.8628807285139,234.521429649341,-49.6013721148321));
#660=CARTESIAN_POINT('',(51.6263142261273,244.16111088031,-53.1982993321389));
#661=CARTESIAN_POINT('',(51.5058923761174,248.972245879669,-55.0208257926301));
#662=CARTESIAN_POINT('',(51.2615061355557,258.552515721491,-58.69562190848));
#663=CARTESIAN_POINT('',(51.1375650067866,263.321735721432,-60.5476714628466));
#664=CARTESIAN_POINT('',(50.885723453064,272.847325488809,-64.2834160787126));
#665=CARTESIAN_POINT('',(50.7578232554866,277.603695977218,-66.167109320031));
#666=CARTESIAN_POINT('',(50.4984348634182,287.105745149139,-69.9582656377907));
#667=CARTESIAN_POINT('',(50.3669473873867,291.851425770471,-71.8657239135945));
#668=CARTESIAN_POINT('',(50.1008717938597,301.334224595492,-75.6966061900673));
#669=CARTESIAN_POINT('',(49.9662848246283,306.071345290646,-77.6200241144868));
#670=CARTESIAN_POINT('',(49.6946033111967,315.539127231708,-81.4751282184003));
#671=CARTESIAN_POINT('',(49.5575101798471,320.269790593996,-83.406809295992));
#672=CARTESIAN_POINT('',(49.4194094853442,325.,-85.3394887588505));
#673=B_SPLINE_CURVE_WITH_KNOTS('',3,(#621,#622,#623,#624,#625,#626,#627,#628,#629,#630,#631,
#632,#633,#634,#635,#636,#637,#638,#639,#640,#641,#642,#643,#644,#645,#646,#647,#648,#649,#650,
#651,#652,#653,#654,#655,#656,#657,#658,#659,#660,#661,#662,#663,#664,#665,#666,#667,#668,#669,
#670,#671,#672),.UNSPECIFIED.,.F.,.F.,(4,2,2,2,2,2,2,2,2,2,2,2,2,2,2,2,2,2,2,2,2,2,2,2,2,4),(0.,
5.55007084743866,11.1001102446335,22.1957701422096,33.2893449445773,44.3824246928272,
55.4308111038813,66.4800292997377,77.5298918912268,88.5796586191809,103.28812436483,
117.996107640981,132.704112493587,147.444472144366,162.184675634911,176.924279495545,
192.3563533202,207.788723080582,223.222854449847,238.659253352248,254.097565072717,
269.450538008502,284.802630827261,300.151671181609,315.495113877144,330.830158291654),.UNSPECIFIED.);
#674=EDGE_CURVE('E175',#404,#36,#673,.T.);
#675=ORIENTED_EDGE('',*,*,#674,.F.);
#676=EDGE_LOOP('',(#618,#619,#620,#675));
#677=FACE_BOUND('',#676,.T.);
#678=ADVANCED_FACE('F170',(#677),#617,.F.);
#679=CARTESIAN_POINT('',(-57.7350269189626,0.,0.));
#680=CARTESIAN_POINT('',(-57.7350269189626,112.216721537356,0.));
#681=CARTESIAN_POINT('',(-54.1265877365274,218.608360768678,43.75));
#682=CARTESIAN_POINT('',(-50.5181485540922,325.,87.5));
#683=CARTESIAN_POINT('',(-48.1125224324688,0.,16.6666666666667));
#684=CARTESIAN_POINT('',(-48.1125224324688,112.216721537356,16.6666666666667));
#685=CARTESIAN_POINT('',(-32.4759526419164,218.608360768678,52.0833333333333));
#686=CARTESIAN_POINT('',(-16.839382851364,325.,87.5));
#687=CARTESIAN_POINT('',(-38.490017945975,0.,33.3333333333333));
#688=CARTESIAN_POINT('',(-38.490017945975,112.216721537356,33.3333333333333));
#689=CARTESIAN_POINT('',(-10.8253175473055,218.608360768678,60.4166666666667));
#690=CARTESIAN_POINT('',(16.8393828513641,325.,87.5));
#691=CARTESIAN_POINT('',(-28.8675134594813,0.,50.));
#692=CARTESIAN_POINT('',(-28.8675134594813,112.216721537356,50.));
#693=CARTESIAN_POINT('',(10.8253175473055,218.608360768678,68.75));
#694=CARTESIAN_POINT('',(50.5181485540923,325.,87.5));
#695=B_SPLINE_SURFACE_WITH_KNOTS('',3,3,((#679,#680,#681,#682),(#683,#684,#685,#686),(#687,#688,
#689,#690),(#691,#692,#693,#694)),.UNSPECIFIED.,.F.,.F.,.F.,(4,4),(4,4),(0.,1.),(0.,1.),.UNSPECIFIED.);
#696=OFFSET_SURFACE('',#695,-2.,.F.);
#697=ORIENTED_EDGE('',*,*,#440,.F.);
#698=CARTESIAN_POINT('',(-55.4202012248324,7.49999999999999,0.0622549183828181));
#699=CARTESIAN_POINT('',(-55.4175338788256,9.34979276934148,0.0928811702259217));
#700=CARTESIAN_POINT('',(-55.4138875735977,11.1993772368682,0.134749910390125));
#701=CARTESIAN_POINT('',(-55.4046725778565,14.8978964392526,0.240663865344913));
#702=CARTESIAN_POINT('',(-55.3991038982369,16.7468311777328,0.304708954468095));
#703=CARTESIAN_POINT('',(-55.379572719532,22.2908707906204,0.529587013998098));
#704=CARTESIAN_POINT('',(-55.3627828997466,25.9846841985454,0.723187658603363));
#705=CARTESIAN_POINT('',(-55.3220163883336,33.3661046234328,1.19501697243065));
#706=CARTESIAN_POINT('',(-55.298041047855,37.0537126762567,1.47322973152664));
#707=CARTESIAN_POINT('',(-55.2433208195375,44.421628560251,2.11132783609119));
#708=CARTESIAN_POINT('',(-55.2125762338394,48.1019367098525,2.47120953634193));
#709=CARTESIAN_POINT('',(-55.1449283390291,55.4391292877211,3.26791913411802));
#710=CARTESIAN_POINT('',(-55.108050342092,59.0960483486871,3.70443117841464));
#711=CARTESIAN_POINT('',(-55.0285640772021,66.4003826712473,4.65220934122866));
#712=CARTESIAN_POINT('',(-54.9859553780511,70.0477971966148,5.16348108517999));
#713=CARTESIAN_POINT('',(-54.8955610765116,77.3320241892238,6.25751605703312));
#714=CARTESIAN_POINT('',(-54.8477751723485,80.9688360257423,6.8402834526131));
#715=CARTESIAN_POINT('',(-54.7476040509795,88.2307496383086,8.07398715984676));
#716=CARTESIAN_POINT('',(-54.6952188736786,91.8558515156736,8.72492288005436));
#717=CARTESIAN_POINT('',(-54.5684156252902,100.292044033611,10.3179871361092));
#718=CARTESIAN_POINT('',(-54.4924454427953,105.098392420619,11.2851678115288));
#719=CARTESIAN_POINT('',(-54.3346871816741,114.687877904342,13.3269226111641));
#720=CARTESIAN_POINT('',(-54.2528992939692,119.471015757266,14.4014932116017));
#721=CARTESIAN_POINT('',(-54.0846409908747,129.013580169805,16.6507353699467));
#722=CARTESIAN_POINT('',(-53.9981705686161,133.773006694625,17.8254070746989));
#723=CARTESIAN_POINT('',(-53.821233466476,143.278258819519,20.270451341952));
#724=CARTESIAN_POINT('',(-53.7307584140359,148.02403146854,21.5410287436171));
#725=CARTESIAN_POINT('',(-53.546557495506,157.491418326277,24.1686550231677));
#726=CARTESIAN_POINT('',(-53.4528316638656,162.213032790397,25.5257029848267));
#727=CARTESIAN_POINT('',(-53.2623738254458,171.632346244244,28.3193862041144));
#728=CARTESIAN_POINT('',(-53.1656419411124,176.330046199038,29.7560182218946));
#729=CARTESIAN_POINT('',(-52.9645233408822,185.922623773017,32.7712986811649));
#730=CARTESIAN_POINT('',(-52.859990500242,190.816396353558,34.3534482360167));
#731=CARTESIAN_POINT('',(-52.6473547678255,200.580076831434,37.5896919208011));
#732=CARTESIAN_POINT('',(-52.5392518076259,205.449984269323,39.2437874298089));
#733=CARTESIAN_POINT('',(-52.3191563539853,215.168042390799,42.6161060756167));
#734=CARTESIAN_POINT('',(-52.2071634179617,220.016190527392,44.3343365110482));
#735=CARTESIAN_POINT('',(-51.9790259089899,229.692885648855,47.8269654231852));
#736=CARTESIAN_POINT('',(-51.8628807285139,234.521429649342,49.6013721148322));
#737=CARTESIAN_POINT('',(-51.6263142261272,244.16111088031,53.198299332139));
#738=CARTESIAN_POINT('',(-51.5058923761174,248.972245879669,55.0208257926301));
#739=CARTESIAN_POINT('',(-51.2615061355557,258.552515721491,58.6956219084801));
#740=CARTESIAN_POINT('',(-51.1375650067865,263.321735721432,60.5476714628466));
#741=CARTESIAN_POINT('',(-50.885723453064,272.847325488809,64.2834160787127));
#742=CARTESIAN_POINT('',(-50.7578232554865,277.603695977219,66.1671093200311));
#743=CARTESIAN_POINT('',(-50.4984348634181,287.105745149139,69.9582656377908));
#744=CARTESIAN_POINT('',(-50.3669473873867,291.851425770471,71.8657239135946));
#745=CARTESIAN_POINT('',(-50.1008717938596,301.334224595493,75.6966061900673));
#746=CARTESIAN_POINT('',(-49.9662848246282,306.071345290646,77.6200241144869));
#747=CARTESIAN_POINT('',(-49.6946033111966,315.539127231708,81.4751282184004));
#748=CARTESIAN_POINT('',(-49.557510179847,320.269790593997,83.406809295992));
#749=CARTESIAN_POINT('',(-49.4194094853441,325.,85.3394887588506));
#750=B_SPLINE_CURVE_WITH_KNOTS('',3,(#698,#699,#700,#701,#702,#703,#704,#705,#706,#707,#708,
#709,#710,#711,#712,#713,#714,#715,#716,#717,#718,#719,#720,#721,#722,#723,#724,#725,#726,#727,
#728,#729,#730,#731,#732,#733,#734,#735,#736,#737,#738,#739,#740,#741,#742,#743,#744,#745,#746,
#747,#748,#749),.UNSPECIFIED.,.F.,.F.,(4,2,2,2,2,2,2,2,2,2,2,2,2,2,2,2,2,2,2,2,2,2,2,2,2,4),(0.,
5.55007084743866,11.1001102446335,22.1957701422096,33.2893449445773,44.3824246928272,
55.4308111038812,66.4800292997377,77.5298918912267,88.5796586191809,103.28812436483,
117.996107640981,132.704112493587,147.444472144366,162.184675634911,176.924279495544,
192.356353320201,207.788723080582,223.222854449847,238.659253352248,254.097565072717,
269.450538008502,284.802630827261,300.151671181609,315.495113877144,330.830158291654),.UNSPECIFIED.);
#751=EDGE_CURVE('E518',#428,#62,#750,.T.);
#752=ORIENTED_EDGE('',*,*,#751,.T.);
#753=ORIENTED_EDGE('',*,*,#63,.T.);
#754=ORIENTED_EDGE('',*,*,#539,.T.);
#755=EDGE_LOOP('',(#697,#752,#753,#754));
#756=FACE_BOUND('',#755,.T.);
#757=ADVANCED_FACE('F221',(#756),#696,.F.);
#758=CARTESIAN_POINT('',(57.7350269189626,0.,0.));
#759=CARTESIAN_POINT('',(57.7350269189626,112.216721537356,0.));
#760=CARTESIAN_POINT('',(54.1265877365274,218.608360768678,-43.75));
#761=CARTESIAN_POINT('',(50.5181485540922,325.,-87.5));
#762=CARTESIAN_POINT('',(48.1125224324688,0.,-16.6666666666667));
#763=CARTESIAN_POINT('',(48.1125224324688,112.216721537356,-16.6666666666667));
#764=CARTESIAN_POINT('',(32.4759526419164,218.608360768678,-52.0833333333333));
#765=CARTESIAN_POINT('',(16.8393828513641,325.,-87.5));
#766=CARTESIAN_POINT('',(38.4900179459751,0.,-33.3333333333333));
#767=CARTESIAN_POINT('',(38.4900179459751,112.216721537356,-33.3333333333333));
#768=CARTESIAN_POINT('',(10.8253175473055,218.608360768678,-60.4166666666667));
#769=CARTESIAN_POINT('',(-16.8393828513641,325.,-87.5));
#770=CARTESIAN_POINT('',(28.8675134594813,0.,-50.));
#771=CARTESIAN_POINT('',(28.8675134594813,112.216721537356,-50.));
#772=CARTESIAN_POINT('',(-10.8253175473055,218.608360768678,-68.75));
#773=CARTESIAN_POINT('',(-50.5181485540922,325.,-87.5));
#774=B_SPLINE_SURFACE_WITH_KNOTS('',3,3,((#758,#759,#760,#761),(#762,#763,#764,#765),(#766,#767,
#768,#769),(#770,#771,#772,#773)),.UNSPECIFIED.,.F.,.F.,.F.,(4,4),(4,4),(0.,1.),(0.,1.),.UNSPECIFIED.);
#775=OFFSET_SURFACE('',#774,-2.,.F.);
#776=ORIENTED_EDGE('',*,*,#407,.F.);
#777=ORIENTED_EDGE('',*,*,#674,.T.);
#778=ORIENTED_EDGE('',*,*,#100,.T.);
#779=CARTESIAN_POINT('',(27.6561862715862,7.49999999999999,-48.0264296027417));
#780=CARTESIAN_POINT('',(27.628329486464,9.34979276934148,-48.0394327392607));
#781=CARTESIAN_POINT('',(27.5902469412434,11.1993772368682,-48.0572093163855));
#782=CARTESIAN_POINT('',(27.4939152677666,14.8978964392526,-48.1021858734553));
#783=CARTESIAN_POINT('',(27.4356662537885,16.7468311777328,-48.1293858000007));
#784=CARTESIAN_POINT('',(27.2311505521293,22.2908707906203,-48.2249103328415));
#785=CARTESIAN_POINT('',(27.0550925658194,25.9846841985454,-48.307170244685));
#786=CARTESIAN_POINT('',(26.6260931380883,33.3661046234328,-48.5077800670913));
#787=CARTESIAN_POINT('',(26.3731661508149,37.0537126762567,-48.6261231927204));
#788=CARTESIAN_POINT('',(25.7931968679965,44.421628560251,-48.8977831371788));
#789=CARTESIAN_POINT('',(25.4661578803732,48.1019367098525,-49.0510983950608));
#790=CARTESIAN_POINT('',(24.742363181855,55.4391292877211,-49.3908683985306));
#791=CARTESIAN_POINT('',(24.3458936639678,59.0960483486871,-49.5771871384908));
#792=CARTESIAN_POINT('',(23.4853505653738,66.4003826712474,-49.9822390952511));
#793=CARTESIAN_POINT('',(23.0212718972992,70.0477971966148,-50.2009747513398));
#794=CARTESIAN_POINT('',(22.028612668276,77.3320241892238,-50.6697084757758));
#795=CARTESIAN_POINT('',(21.500028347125,80.9688360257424,-50.9197083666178));
#796=CARTESIAN_POINT('',(20.3815240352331,88.2307496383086,-51.4498094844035));
#797=CARTESIAN_POINT('',(19.7916045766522,91.8558515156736,-51.7299104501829));
#798=CARTESIAN_POINT('',(18.3485688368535,100.292044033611,-52.4166277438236));
#799=CARTESIAN_POINT('',(17.4729807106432,105.098392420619,-52.8344259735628));
#800=CARTESIAN_POINT('',(15.6258900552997,114.687877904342,-53.7186807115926));
#801=CARTESIAN_POINT('',(14.6543906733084,119.471015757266,-54.185135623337));
#802=CARTESIAN_POINT('',(12.6223606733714,129.013580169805,-55.164040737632));
#803=CARTESIAN_POINT('',(11.56182992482,133.773006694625,-55.6764910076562));
#804=CARTESIAN_POINT('',(9.35589092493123,143.278258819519,-56.7457811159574));
#805=CARTESIAN_POINT('',(8.21030109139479,148.02403146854,-57.3027161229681));
#806=CARTESIAN_POINT('',(5.84260952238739,157.491418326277,-58.4570065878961));
#807=CARTESIAN_POINT('',(4.62050859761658,162.213032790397,-59.0543616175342));
#808=CARTESIAN_POINT('',(2.10587904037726,171.632346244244,-60.2862619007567));
#809=CARTESIAN_POINT('',(0.813353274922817,176.330046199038,-60.9208056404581));
#810=CARTESIAN_POINT('',(-1.89851550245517,185.922623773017,-62.2542720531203));
#811=CARTESIAN_POINT('',(-3.32096362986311,190.816396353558,-62.9548187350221));
#812=CARTESIAN_POINT('',(-6.22995073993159,200.580076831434,-64.3887926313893));
#813=CARTESIAN_POINT('',(-7.71649095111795,205.449984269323,-65.122220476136));
#814=CARTESIAN_POINT('',(-10.7470522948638,215.168042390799,-66.6177715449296));
#815=CARTESIAN_POINT('',(-12.2910799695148,220.016190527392,-67.3798980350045));
#816=CARTESIAN_POINT('',(-15.4298540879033,229.692885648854,-68.9286396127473));
#817=CARTESIAN_POINT('',(-17.0246079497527,234.521429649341,-69.7152582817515));
#818=CARTESIAN_POINT('',(-20.2579215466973,244.16111088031,-71.3088492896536));
#819=CARTESIAN_POINT('',(-21.896486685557,248.972245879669,-72.1158241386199));
#820=CARTESIAN_POINT('',(-25.2011465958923,258.552515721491,-73.7415775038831));
#821=CARTESIAN_POINT('',(-26.8670391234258,263.321735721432,-74.5602661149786));
#822=CARTESIAN_POINT('',(-30.228209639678,272.847325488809,-76.2100372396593));
#823=CARTESIAN_POINT('',(-31.9234859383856,277.603695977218,-77.0411190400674));
#824=CARTESIAN_POINT('',(-35.3364178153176,287.105745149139,-78.7120602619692));
#825=CARTESIAN_POINT('',(-37.0540688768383,291.851425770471,-79.5519179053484));
#826=CARTESIAN_POINT('',(-40.5047480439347,301.334224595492,-81.2369308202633));
#827=CARTESIAN_POINT('',(-42.2377703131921,306.071345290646,-82.0820840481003));
#828=CARTESIAN_POINT('',(-45.7122291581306,315.539127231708,-83.7743530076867));
#829=CARTESIAN_POINT('',(-47.4536606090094,320.269790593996,-84.6214674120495));
#830=CARTESIAN_POINT('',(-49.1964604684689,325.,-85.4682084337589));
#831=B_SPLINE_CURVE_WITH_KNOTS('',3,(#779,#780,#781,#782,#783,#784,#785,#786,#787,#788,#789,
#790,#791,#792,#793,#794,#795,#796,#797,#798,#799,#800,#801,#802,#803,#804,#805,#806,#807,#808,
#809,#810,#811,#812,#813,#814,#815,#816,#817,#818,#819,#820,#821,#822,#823,#824,#825,#826,#827,
#828,#829,#830),.UNSPECIFIED.,.F.,.F.,(4,2,2,2,2,2,2,2,2,2,2,2,2,2,2,2,2,2,2,2,2,2,2,2,2,4),(0.,
5.55007084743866,11.1001102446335,22.1957701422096,33.2893449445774,44.3824246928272,
55.4308111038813,66.4800292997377,77.5298918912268,88.5796586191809,103.28812436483,
117.996107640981,132.704112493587,147.444472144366,162.184675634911,176.924279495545,
192.356353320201,207.788723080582,223.222854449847,238.659253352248,254.097565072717,
269.450538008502,284.80263082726,300.151671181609,315.495113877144,330.830158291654),.UNSPECIFIED.);
#832=EDGE_CURVE('E192',#406,#88,#831,.T.);
#833=ORIENTED_EDGE('',*,*,#832,.F.);
#834=EDGE_LOOP('',(#776,#777,#778,#833));
#835=FACE_BOUND('',#834,.T.);
#836=ADVANCED_FACE('F222',(#835),#775,.F.);
#837=CARTESIAN_POINT('',(28.8675134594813,0.,-50.));
#838=CARTESIAN_POINT('',(28.8675134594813,112.216721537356,-50.));
#839=CARTESIAN_POINT('',(-10.8253175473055,218.608360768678,-68.75));
#840=CARTESIAN_POINT('',(-50.5181485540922,325.,-87.5));
#841=CARTESIAN_POINT('',(9.62250448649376,0.,-50.));
#842=CARTESIAN_POINT('',(9.62250448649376,112.216721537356,-50.));
#843=CARTESIAN_POINT('',(-28.8675134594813,218.608360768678,-54.1666666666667));
#844=CARTESIAN_POINT('',(-67.3575314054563,325.,-58.3333333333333));
#845=CARTESIAN_POINT('',(-9.62250448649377,0.,-50.));
#846=CARTESIAN_POINT('',(-9.62250448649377,112.216721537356,-50.));
#847=CARTESIAN_POINT('',(-46.9097093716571,218.608360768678,-39.5833333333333));
#848=CARTESIAN_POINT('',(-84.1969142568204,325.,-29.1666666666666));
#849=CARTESIAN_POINT('',(-28.8675134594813,0.,-50.));
#850=CARTESIAN_POINT('',(-28.8675134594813,112.216721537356,-50.));
#851=CARTESIAN_POINT('',(-64.9519052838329,218.608360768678,-25.));
#852=CARTESIAN_POINT('',(-101.036297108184,325.,0.));
#853=B_SPLINE_SURFACE_WITH_KNOTS('',3,3,((#837,#838,#839,#840),(#841,#842,#843,#844),(#845,#846,
#847,#848),(#849,#850,#851,#852)),.UNSPECIFIED.,.F.,.F.,.F.,(4,4),(4,4),(0.,1.),(0.,1.),.UNSPECIFIED.);
#854=OFFSET_SURFACE('',#853,-2.,.F.);
#855=ORIENTED_EDGE('',*,*,#418,.F.);
#856=ORIENTED_EDGE('',*,*,#832,.T.);
#857=ORIENTED_EDGE('',*,*,#89,.T.);
#858=CARTESIAN_POINT('',(-27.7640149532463,7.5,-47.9641746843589));
#859=CARTESIAN_POINT('',(-27.7892043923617,9.34979276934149,-47.9465515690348));
#860=CARTESIAN_POINT('',(-27.8236406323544,11.1993772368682,-47.9224594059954));
#861=CARTESIAN_POINT('',(-27.9107573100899,14.8978964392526,-47.8615220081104));
#862=CARTESIAN_POINT('',(-27.9634376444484,16.7468311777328,-47.8246768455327));
#863=CARTESIAN_POINT('',(-28.1484221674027,22.2908707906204,-47.6953233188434));
#864=CARTESIAN_POINT('',(-28.3076903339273,25.9846841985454,-47.5839825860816));
#865=CARTESIAN_POINT('',(-28.6959232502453,33.3661046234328,-47.3127630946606));
#866=CARTESIAN_POINT('',(-28.9248748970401,37.0537126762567,-47.1528934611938));
#867=CARTESIAN_POINT('',(-29.4501239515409,44.421628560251,-46.7864553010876));
#868=CARTESIAN_POINT('',(-29.7464183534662,48.1019367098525,-46.5798888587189));
#869=CARTESIAN_POINT('',(-30.402565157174,55.4391292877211,-46.1229492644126));
#870=CARTESIAN_POINT('',(-30.7621566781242,59.0960483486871,-45.8727559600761));
#871=CARTESIAN_POINT('',(-31.5432135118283,66.4003826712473,-45.3300297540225));
#872=CARTESIAN_POINT('',(-31.9646834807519,70.0477971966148,-45.0374936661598));
#873=CARTESIAN_POINT('',(-32.8669484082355,77.3320241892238,-44.4121924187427));
#874=CARTESIAN_POINT('',(-33.3477468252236,80.9688360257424,-44.0794249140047));
#875=CARTESIAN_POINT('',(-34.3660800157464,88.2307496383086,-43.3758223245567));
#876=CARTESIAN_POINT('',(-34.9036142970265,91.8558515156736,-43.0049875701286));
#877=CARTESIAN_POINT('',(-36.2198467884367,100.292044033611,-42.0986406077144));
#878=CARTESIAN_POINT('',(-37.0194647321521,105.098392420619,-41.5492581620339));
#879=CARTESIAN_POINT('',(-38.7087971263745,114.687877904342,-40.3917581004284));
#880=CARTESIAN_POINT('',(-39.5985086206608,119.471015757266,-39.7836424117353));
#881=CARTESIAN_POINT('',(-41.4622803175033,129.013580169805,-38.5133053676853));
#882=CARTESIAN_POINT('',(-42.4363406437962,133.773006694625,-37.8510839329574));
#883=CARTESIAN_POINT('',(-44.4653425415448,143.278258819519,-36.4753297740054));
#884=CARTESIAN_POINT('',(-45.5204573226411,148.02403146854,-35.761687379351));
#885=CARTESIAN_POINT('',(-47.7039479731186,157.491418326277,-34.2883515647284));
#886=CARTESIAN_POINT('',(-48.832323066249,162.213032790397,-33.5286586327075));
#887=CARTESIAN_POINT('',(-51.1564947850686,171.632346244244,-31.9668756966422));
#888=CARTESIAN_POINT('',(-52.3522886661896,176.330046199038,-31.1647874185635));
#889=CARTESIAN_POINT('',(-54.8630388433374,185.922623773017,-29.4829733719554));
#890=CARTESIAN_POINT('',(-56.1809541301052,190.816396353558,-28.6013704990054));
#891=CARTESIAN_POINT('',(-58.8773055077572,200.580076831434,-26.7991007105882));
#892=CARTESIAN_POINT('',(-60.2557427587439,205.449984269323,-25.8784330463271));
#893=CARTESIAN_POINT('',(-63.0662086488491,215.168042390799,-24.0016654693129));
#894=CARTESIAN_POINT('',(-64.4982433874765,220.016190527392,-23.0455615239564));
#895=CARTESIAN_POINT('',(-67.4088799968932,229.692885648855,-21.1016741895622));
#896=CARTESIAN_POINT('',(-68.8874886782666,234.521429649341,-20.1138861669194));
#897=CARTESIAN_POINT('',(-71.8842357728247,244.16111088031,-18.1105499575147));
#898=CARTESIAN_POINT('',(-73.4023790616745,248.972245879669,-17.0949983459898));
#899=CARTESIAN_POINT('',(-76.462652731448,258.552515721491,-15.045955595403));
#900=CARTESIAN_POINT('',(-78.0046041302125,263.321735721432,-14.012594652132));
#901=CARTESIAN_POINT('',(-81.1139330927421,272.847325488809,-11.9266211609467));
#902=CARTESIAN_POINT('',(-82.6813091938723,277.603695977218,-10.8740097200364));
#903=CARTESIAN_POINT('',(-85.8348526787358,287.105745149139,-8.75379462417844));
#904=CARTESIAN_POINT('',(-87.421016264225,291.851425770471,-7.68619399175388));
#905=CARTESIAN_POINT('',(-90.6056198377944,301.334224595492,-5.54032463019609));
#906=CARTESIAN_POINT('',(-92.2040551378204,306.071345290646,-4.46205993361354));
#907=CARTESIAN_POINT('',(-95.4068324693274,315.539127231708,-2.29922478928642));
#908=CARTESIAN_POINT('',(-97.0111707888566,320.269790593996,-1.21465811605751));
#909=CARTESIAN_POINT('',(-98.6158699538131,325.,-0.128719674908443));
#910=B_SPLINE_CURVE_WITH_KNOTS('',3,(#858,#859,#860,#861,#862,#863,#864,#865,#866,#867,#868,
#869,#870,#871,#872,#873,#874,#875,#876,#877,#878,#879,#880,#881,#882,#883,#884,#885,#886,#887,
#888,#889,#890,#891,#892,#893,#894,#895,#896,#897,#898,#899,#900,#901,#902,#903,#904,#905,#906,
#907,#908,#909),.UNSPECIFIED.,.F.,.F.,(4,2,2,2,2,2,2,2,2,2,2,2,2,2,2,2,2,2,2,2,2,2,2,2,2,4),(0.,
5.55007084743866,11.1001102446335,22.1957701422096,33.2893449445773,44.3824246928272,
55.4308111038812,66.4800292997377,77.5298918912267,88.5796586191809,103.28812436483,
117.996107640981,132.704112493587,147.444472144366,162.184675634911,176.924279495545,
192.356353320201,207.788723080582,223.222854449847,238.659253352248,254.097565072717,
269.450538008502,284.802630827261,300.151671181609,315.495113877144,330.830158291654),.UNSPECIFIED.);
#911=EDGE_CURVE('E526',#417,#75,#910,.T.);
#912=ORIENTED_EDGE('',*,*,#911,.F.);
#913=EDGE_LOOP('',(#855,#856,#857,#912));
#914=FACE_BOUND('',#913,.T.);
#915=ADVANCED_FACE('F423',(#914),#854,.F.);
#916=CARTESIAN_POINT('',(-28.8675134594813,0.,-50.));
#917=CARTESIAN_POINT('',(-28.8675134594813,112.216721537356,-50.));
#918=CARTESIAN_POINT('',(-64.9519052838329,218.608360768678,-25.));
#919=CARTESIAN_POINT('',(-101.036297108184,325.,0.));
#920=CARTESIAN_POINT('',(-38.4900179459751,0.,-33.3333333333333));
#921=CARTESIAN_POINT('',(-38.4900179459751,112.216721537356,-33.3333333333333));
#922=CARTESIAN_POINT('',(-61.3434661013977,218.608360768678,-2.08333333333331));
#923=CARTESIAN_POINT('',(-84.1969142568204,325.,29.1666666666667));
#924=CARTESIAN_POINT('',(-48.1125224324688,0.,-16.6666666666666));
#925=CARTESIAN_POINT('',(-48.1125224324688,112.216721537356,-16.6666666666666));
#926=CARTESIAN_POINT('',(-57.7350269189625,218.608360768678,20.8333333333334));
#927=CARTESIAN_POINT('',(-67.3575314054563,325.,58.3333333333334));
#928=CARTESIAN_POINT('',(-57.7350269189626,0.,0.));
#929=CARTESIAN_POINT('',(-57.7350269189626,112.216721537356,0.));
#930=CARTESIAN_POINT('',(-54.1265877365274,218.608360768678,43.75));
#931=CARTESIAN_POINT('',(-50.5181485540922,325.,87.5));
#932=B_SPLINE_SURFACE_WITH_KNOTS('',3,3,((#916,#917,#918,#919),(#920,#921,#922,#923),(#924,#925,
#926,#927),(#928,#929,#930,#931)),.UNSPECIFIED.,.F.,.F.,.F.,(4,4),(4,4),(0.,1.),(0.,1.),.UNSPECIFIED.);
#933=OFFSET_SURFACE('',#932,-2.,.F.);
#934=ORIENTED_EDGE('',*,*,#429,.F.);
#935=ORIENTED_EDGE('',*,*,#911,.T.);
#936=ORIENTED_EDGE('',*,*,#76,.T.);
#937=ORIENTED_EDGE('',*,*,#751,.F.);
#938=EDGE_LOOP('',(#934,#935,#936,#937));
#939=FACE_BOUND('',#938,.T.);
#940=ADVANCED_FACE('F371',(#939),#933,.F.);
#941=CLOSED_SHELL('',(#154,#210,#246,#276,#306,#336,#366,#390,#464,#599,#678,#757,#836,#915,#940));
#942=MANIFOLD_SOLID_BREP('B2',#941);
#943=ADVANCED_BREP_SHAPE_REPRESENTATION('',(#18,#942),#14);
#944=SHAPE_DEFINITION_REPRESENTATION(#9,#943);
ENDSEC;
END-ISO-10303-21;
